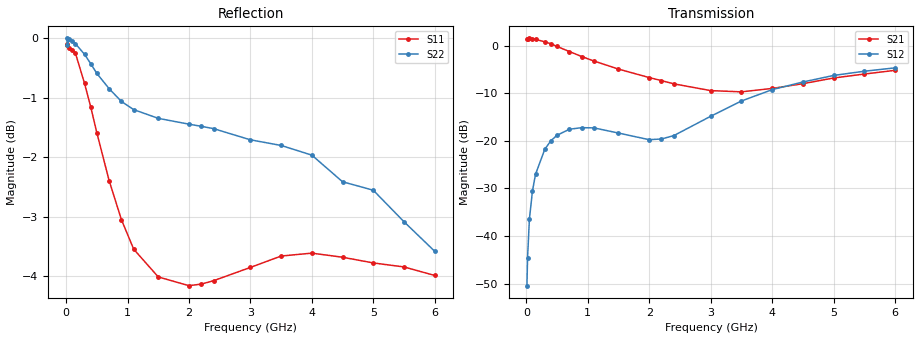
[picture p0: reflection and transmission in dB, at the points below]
! Infineon Technologies  Discrete & RF Semiconductors
! BFS17W
! Si NPN RF Bipolar Junction Transistor in SOT323
! VCE = 12 V  IC = 0.3 mA
! Common Emitter S-Parameters:  August  1999
# GHz  S  MA  R  50
!  f  S11  S21  S12  S22
! GHz  MAG  ANG  MAG  ANG  MAG  ANG  MAG  ANG
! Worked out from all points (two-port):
!   36 points, 10 MHz to 6 GHz, reference 50 ohm
!   highest |S21| = 1.53 dB at 50 MHz (marker M1); lowest = -9.7 dB at 3.5 GHz (marker M2)
!   |S21| within 3 dB of the highest: start of sweep to 746.1 MHz
!   lowest |S11| = -4.2 dB at 2 GHz (marker M3), VSWR 4.25, Z = 11.8 + j1.61 ohm
!   |S11| at or under -10 dB: nowhere
!   |S22| runs from -3.6 to 0.0 dB; largest |S21 - S12| = 1.2
!   S11 on the Smith chart (normalised r, x): 10 MHz: 33, -65; 300 MHz: 0.28, -2.33; 700 MHz: 0.25, -0.88; 1.5 GHz: 0.24, -0.18; 3 GHz: 0.25, +0.37; 6 GHz: 0.55, +1.11
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0.01  0.9878 -1.4  1.187 179.5  0.003 84.4  0.9999 0.1
0.02  0.9896 -3.3  1.186 177.6  0.0059 93.3  0.9862 -0.7
0.05  0.9818 -7.8  1.193 173.4  0.015 85.0  0.9981 -1.9
0.1  0.9773 -15.5  1.173 167.2  0.0298 80.2  0.9949 -3.8
0.15  0.9722 -24.1  1.168 160.3  0.0445 75.6  0.9899 -5.7
0.3  0.9164 -46.0  1.095 141.7  0.0814 63.0  0.9694 -10.7
0.4  0.8759 -59.8  1.047 130.2  0.1003 55.0  0.9522 -13.8
0.5  0.8329 -72.4  0.98 120.1  0.1143 48.4  0.9343 -16.5
0.7  0.7592 -95.2  0.868 102.3  0.1322 38.3  0.9071 -21.3
0.9  0.7039 -114.5  0.769 88.0  0.1374 30.9  0.8849 -25.9
1.1  0.6647 -131.1  0.69 75.9  0.1367 26.3  0.871 -30.4
1.5  0.6299 -157.9  0.567 57.8  0.1206 24.2  0.8564 -39.5
2  0.6193 176.1  0.462 43.3  0.1027 38.5  0.8468 -52.0
2.2  0.6212 167.5  0.429 39.4  0.1045 48.8  0.8433 -57.2
2.4  0.6253 159.3  0.397 36.9  0.1133 59.1  0.8395 -62.7
3  0.6416 137.3  0.337 36.2  0.1809 75.0  0.8215 -78.6
3.5  0.6559 121.8  0.327 40.8  0.2617 74.5  0.8126 -92.8
4  0.6596 108.8  0.355 44.8  0.3446 68.7  0.7975 -108.3
4.5  0.6544 97.7  0.398 45.2  0.4147 61.0  0.7574 -123.2
5  0.6472 89.2  0.457 42.7  0.486 53.4  0.7451 -137.0
5.5  0.6422 82.0  0.503 38.4  0.5386 45.6  0.701 -151.2
6  0.6317 76.4  0.55 33.6  0.584 38.6  0.662 -163.6
